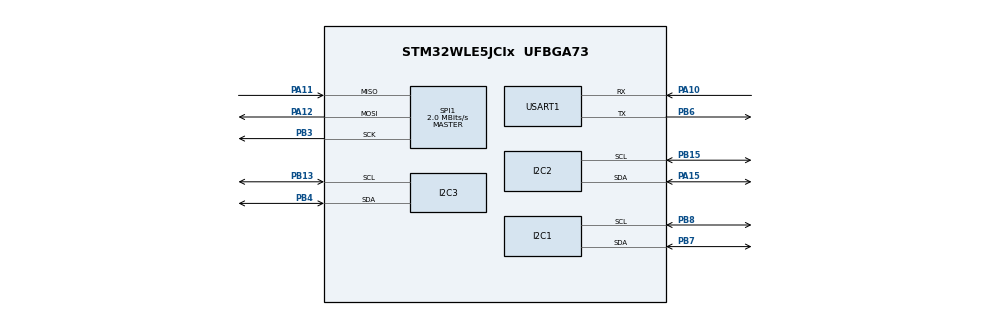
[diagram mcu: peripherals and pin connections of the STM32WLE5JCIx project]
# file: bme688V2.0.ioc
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Mcu.Family=STM32WL
Mcu.Name=STM32WLE5JCIx
Mcu.Package=UFBGA73
NVIC.PriorityGroup=NVIC_PRIORITYGROUP_4
OSC_IN.Mode=HSE-External-Oscillator
OSC_IN.Signal=RCC_OSC_IN
OSC_OUT.Mode=HSE-External-Oscillator
OSC_OUT.Signal=RCC_OSC_OUT
PA10.Mode=Asynchronous
PA10.Signal=USART1_RX
PA11.Mode=Full_Duplex_Master
PA11.Signal=SPI1_MISO
PA12.Mode=Full_Duplex_Master
PA12.Signal=SPI1_MOSI
PA15.Mode=I2C
PA15.Signal=I2C2_SDA
PB13.Mode=I2C
PB13.Signal=I2C3_SCL
PB15.Mode=I2C
PB15.Signal=I2C2_SCL
PB3.Mode=Full_Duplex_Master
PB3.Signal=SPI1_SCK
PB4.Mode=I2C
PB4.Signal=I2C3_SDA
PB6.Mode=Asynchronous
PB6.Signal=USART1_TX
PB7.Mode=I2C
PB7.Signal=I2C1_SDA
PB8.Mode=I2C
PB8.Signal=I2C1_SCL
ProjectManager.HeapSize=0x200
ProjectManager.StackSize=0x400
ProjectManager.TargetToolchain=STM32CubeIDE
RCC.HSE_VALUE=8000000
RCC.HSI_VALUE=16000000
RCC.LSE_VALUE=32768
RCC.VCOOutputFreq_Value=32000000
SPI1.CalculateBaudRate=2.0 MBits/s
SPI1.Direction=SPI_DIRECTION_2LINES
SPI1.Mode=SPI_MODE_MASTER
SPI1.VirtualType=VM_MASTER
USART1.VirtualMode-Asynchronous=VM_ASYNC
board=custom

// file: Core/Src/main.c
/* USER CODE BEGIN Header */
/**
  ******************************************************************************
  * @file           : main.c
  * @brief          : Main program body
  ******************************************************************************
  * @attention
  *
  * Copyright (c) 2022 STMicroelectronics.
  * All rights reserved.
  *
  * This software is licensed under terms that can be found in the LICENSE file
  * in the root directory of this software component.
  * If no LICENSE file comes with this software, it is provided AS-IS.
  *
  ******************************************************************************
  */
/* USER CODE END Header */
#include "main.h"

/* USER CODE BEGIN Includes */
#include "BME280_STM32.h"
/* USER CODE END Includes */

I2C_HandleTypeDef hi2c1;
I2C_HandleTypeDef hi2c2;
I2C_HandleTypeDef hi2c3;

SPI_HandleTypeDef hspi1;

UART_HandleTypeDef huart1;

void SystemClock_Config(void);
static void MX_GPIO_Init(void);
static void MX_I2C1_Init(void);
static void MX_SPI1_Init(void);
static void MX_USART1_UART_Init(void);
static void MX_I2C2_Init(void);
static void MX_I2C3_Init(void);

/* USER CODE BEGIN 0 */

float Temperature, Pressure, Humidity;
float temp,hum,press;

/* USER CODE END 0 */

int main(void)
{

  /* MCU Configuration--------------------------------------------------------*/

  /* Reset of all peripherals, Initializes the Flash interface and the Systick. */
  HAL_Init();

  /* Configure the system clock */
  SystemClock_Config();

  /* Initialize all configured peripherals */
  MX_GPIO_Init();
  MX_I2C1_Init();
  MX_SPI1_Init();
  MX_USART1_UART_Init();
  MX_I2C2_Init();
  MX_I2C3_Init();
  /* USER CODE BEGIN 2 */

  BME280_Config(OSRS_2, OSRS_16, OSRS_1, MODE_NORMAL, T_SB_0p5, IIR_16);

  /* USER CODE END 2 */

  /* Infinite loop */
  while (1)
  {

    /* USER CODE BEGIN 3 */
	  BME280_Measure();
	  temp=Temperature;
	  hum=Pressure;
	  press=Humidity;
	  HAL_Delay (500);
  }
  /* USER CODE END 3 */
}

void SystemClock_Config(void)
{
  RCC_OscInitTypeDef RCC_OscInitStruct = {0};
  RCC_ClkInitTypeDef RCC_ClkInitStruct = {0};

  /** Configure the main internal regulator output voltage
  */
  __HAL_PWR_VOLTAGESCALING_CONFIG(PWR_REGULATOR_VOLTAGE_SCALE2);

  /** Initializes the CPU, AHB and APB buses clocks
  */
  RCC_OscInitStruct.OscillatorType = RCC_OSCILLATORTYPE_MSI;
  RCC_OscInitStruct.MSIState = RCC_MSI_ON;
  RCC_OscInitStruct.MSICalibrationValue = RCC_MSICALIBRATION_DEFAULT;
  RCC_OscInitStruct.MSIClockRange = RCC_MSIRANGE_6;
  RCC_OscInitStruct.PLL.PLLState = RCC_PLL_NONE;
  if (HAL_RCC_OscConfig(&RCC_OscInitStruct) != HAL_OK)
  {
    Error_Handler();
  }

  /** Configure the SYSCLKSource, HCLK, PCLK1 and PCLK2 clocks dividers
  */
  RCC_ClkInitStruct.ClockType = RCC_CLOCKTYPE_HCLK3|RCC_CLOCKTYPE_HCLK
                              |RCC_CLOCKTYPE_SYSCLK|RCC_CLOCKTYPE_PCLK1
                              |RCC_CLOCKTYPE_PCLK2;
  RCC_ClkInitStruct.SYSCLKSource = RCC_SYSCLKSOURCE_MSI;
  RCC_ClkInitStruct.AHBCLKDivider = RCC_SYSCLK_DIV1;
  RCC_ClkInitStruct.APB1CLKDivider = RCC_HCLK_DIV1;
  RCC_ClkInitStruct.APB2CLKDivider = RCC_HCLK_DIV1;
  RCC_ClkInitStruct.AHBCLK3Divider = RCC_SYSCLK_DIV1;

  if (HAL_RCC_ClockConfig(&RCC_ClkInitStruct, FLASH_LATENCY_0) != HAL_OK)
  {
    Error_Handler();
  }
}

static void MX_I2C1_Init(void)
{

  hi2c1.Instance = I2C1;
  hi2c1.Init.Timing = 0x00000E14;
  hi2c1.Init.OwnAddress1 = 0;
  hi2c1.Init.AddressingMode = I2C_ADDRESSINGMODE_7BIT;
  hi2c1.Init.DualAddressMode = I2C_DUALADDRESS_DISABLE;
  hi2c1.Init.OwnAddress2 = 0;
  hi2c1.Init.OwnAddress2Masks = I2C_OA2_NOMASK;
  hi2c1.Init.GeneralCallMode = I2C_GENERALCALL_DISABLE;
  hi2c1.Init.NoStretchMode = I2C_NOSTRETCH_DISABLE;
  if (HAL_I2C_Init(&hi2c1) != HAL_OK)
  {
    Error_Handler();
  }

  /** Configure Analogue filter
  */
  if (HAL_I2CEx_ConfigAnalogFilter(&hi2c1, I2C_ANALOGFILTER_ENABLE) != HAL_OK)
  {
    Error_Handler();
  }

  /** Configure Digital filter
  */
  if (HAL_I2CEx_ConfigDigitalFilter(&hi2c1, 0) != HAL_OK)
  {
    Error_Handler();
  }

}

static void MX_I2C2_Init(void)
{

  hi2c2.Instance = I2C2;
  hi2c2.Init.Timing = 0x00000E14;
  hi2c2.Init.OwnAddress1 = 0;
  hi2c2.Init.AddressingMode = I2C_ADDRESSINGMODE_7BIT;
  hi2c2.Init.DualAddressMode = I2C_DUALADDRESS_DISABLE;
  hi2c2.Init.OwnAddress2 = 0;
  hi2c2.Init.OwnAddress2Masks = I2C_OA2_NOMASK;
  hi2c2.Init.GeneralCallMode = I2C_GENERALCALL_DISABLE;
  hi2c2.Init.NoStretchMode = I2C_NOSTRETCH_DISABLE;
  if (HAL_I2C_Init(&hi2c2) != HAL_OK)
  {
    Error_Handler();
  }

  /** Configure Analogue filter
  */
  if (HAL_I2CEx_ConfigAnalogFilter(&hi2c2, I2C_ANALOGFILTER_ENABLE) != HAL_OK)
  {
    Error_Handler();
  }

  /** Configure Digital filter
  */
  if (HAL_I2CEx_ConfigDigitalFilter(&hi2c2, 0) != HAL_OK)
  {
    Error_Handler();
  }

}

static void MX_I2C3_Init(void)
{

  hi2c3.Instance = I2C3;
  hi2c3.Init.Timing = 0x00000E14;
  hi2c3.Init.OwnAddress1 = 0;
  hi2c3.Init.AddressingMode = I2C_ADDRESSINGMODE_7BIT;
  hi2c3.Init.DualAddressMode = I2C_DUALADDRESS_DISABLE;
  hi2c3.Init.OwnAddress2 = 0;
  hi2c3.Init.OwnAddress2Masks = I2C_OA2_NOMASK;
  hi2c3.Init.GeneralCallMode = I2C_GENERALCALL_DISABLE;
  hi2c3.Init.NoStretchMode = I2C_NOSTRETCH_DISABLE;
  if (HAL_I2C_Init(&hi2c3) != HAL_OK)
  {
    Error_Handler();
  }

  /** Configure Analogue filter
  */
  if (HAL_I2CEx_ConfigAnalogFilter(&hi2c3, I2C_ANALOGFILTER_ENABLE) != HAL_OK)
  {
    Error_Handler();
  }

  /** Configure Digital filter
  */
  if (HAL_I2CEx_ConfigDigitalFilter(&hi2c3, 0) != HAL_OK)
  {
    Error_Handler();
  }

}

static void MX_SPI1_Init(void)
{

  /* SPI1 parameter configuration*/
  hspi1.Instance = SPI1;
  hspi1.Init.Mode = SPI_MODE_MASTER;
  hspi1.Init.Direction = SPI_DIRECTION_2LINES;
  hspi1.Init.DataSize = SPI_DATASIZE_4BIT;
  hspi1.Init.CLKPolarity = SPI_POLARITY_LOW;
  hspi1.Init.CLKPhase = SPI_PHASE_1EDGE;
  hspi1.Init.NSS = SPI_NSS_SOFT;
  hspi1.Init.BaudRatePrescaler = SPI_BAUDRATEPRESCALER_2;
  hspi1.Init.FirstBit = SPI_FIRSTBIT_MSB;
  hspi1.Init.TIMode = SPI_TIMODE_DISABLE;
  hspi1.Init.CRCCalculation = SPI_CRCCALCULATION_DISABLE;
  hspi1.Init.CRCPolynomial = 7;
  hspi1.Init.CRCLength = SPI_CRC_LENGTH_DATASIZE;
  hspi1.Init.NSSPMode = SPI_NSS_PULSE_ENABLE;
  if (HAL_SPI_Init(&hspi1) != HAL_OK)
  {
    Error_Handler();
  }

}

static void MX_USART1_UART_Init(void)
{

  huart1.Instance = USART1;
  huart1.Init.BaudRate = 115200;
  huart1.Init.WordLength = UART_WORDLENGTH_8B;
  huart1.Init.StopBits = UART_STOPBITS_1;
  huart1.Init.Parity = UART_PARITY_NONE;
  huart1.Init.Mode = UART_MODE_TX_RX;
  huart1.Init.HwFlowCtl = UART_HWCONTROL_NONE;
  huart1.Init.OverSampling = UART_OVERSAMPLING_16;
  huart1.Init.OneBitSampling = UART_ONE_BIT_SAMPLE_DISABLE;
  huart1.Init.ClockPrescaler = UART_PRESCALER_DIV1;
  huart1.AdvancedInit.AdvFeatureInit = UART_ADVFEATURE_NO_INIT;
  if (HAL_UART_Init(&huart1) != HAL_OK)
  {
    Error_Handler();
  }
  if (HAL_UARTEx_SetTxFifoThreshold(&huart1, UART_TXFIFO_THRESHOLD_1_8) != HAL_OK)
  {
    Error_Handler();
  }
  if (HAL_UARTEx_SetRxFifoThreshold(&huart1, UART_RXFIFO_THRESHOLD_1_8) != HAL_OK)
  {
    Error_Handler();
  }
  if (HAL_UARTEx_DisableFifoMode(&huart1) != HAL_OK)
  {
    Error_Handler();
  }

}

static void MX_GPIO_Init(void)
{

	GPIO_InitTypeDef GPIO_InitStruct = {0};

	  /* GPIO Ports Clock Enable */
	  __HAL_RCC_GPIOB_CLK_ENABLE();
	  __HAL_RCC_GPIOA_CLK_ENABLE();

	  /*Configure GPIO pin Output Level */
	  HAL_GPIO_WritePin(GPIOB, GPIO_PIN_5, GPIO_PIN_RESET);
	  HAL_GPIO_WritePin(GPIOB, GPIO_PIN_10, GPIO_PIN_RESET);
	  HAL_GPIO_WritePin(GPIOA, GPIO_PIN_9, GPIO_PIN_RESET);

	  /*Configure GPIO pin : PB5 */
	  GPIO_InitStruct.Pin = GPIO_PIN_5;
	  GPIO_InitStruct.Mode = GPIO_MODE_OUTPUT_PP;
	  GPIO_InitStruct.Pull = GPIO_NOPULL;
	  GPIO_InitStruct.Speed = GPIO_SPEED_FREQ_LOW;
	  HAL_GPIO_Init(GPIOB, &GPIO_InitStruct);

	  GPIO_InitStruct.Pin = GPIO_PIN_9;
	  GPIO_InitStruct.Mode = GPIO_MODE_OUTPUT_PP;
	  GPIO_InitStruct.Pull = GPIO_NOPULL;
	  GPIO_InitStruct.Speed = GPIO_SPEED_FREQ_LOW;
	  HAL_GPIO_Init(GPIOA, &GPIO_InitStruct);

	  HAL_GPIO_WritePin(GPIOA, GPIO_PIN_9, GPIO_PIN_SET);
	 // HAL_GPIO_WritePin(GPIOA, GPIO_PIN_0, GPIO_PIN_SET);
	  /* Initialize GPIOB Pin 10 */

	  GPIO_InitStruct.Pin = GPIO_PIN_10;
	  GPIO_InitStruct.Mode = GPIO_MODE_OUTPUT_PP;
	  GPIO_InitStruct.Pull = GPIO_NOPULL;
	  GPIO_InitStruct.Speed = GPIO_SPEED_FREQ_LOW;
	  HAL_GPIO_Init(GPIOB, &GPIO_InitStruct);

	 	  	 	 /* Set PB10 to high */
	  HAL_GPIO_WritePin(GPIOB, GPIO_PIN_10, GPIO_PIN_SET);

}

void Error_Handler(void)
{
  __disable_irq();
  while (1)
  {
  }
}
